VERSION 5.8 ;
BUSBITCHARS "[]" ;
DIVIDERCHAR "/" ;
UNITS
    DATABASE MICRONS 1000 ;
END UNITS

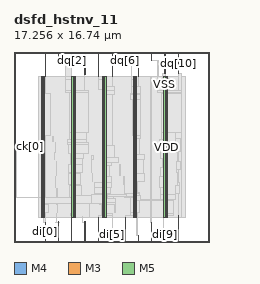
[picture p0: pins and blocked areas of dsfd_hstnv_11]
MACRO dsfd_hstnv_11
  FOREIGN dsfd_hstnv_11 0 0 ;
  CLASS BLOCK ;
  SIZE 17.256 BY 16.74 ;
  PIN ck[0]
    DIRECTION INPUT ;
    USE SIGNAL ;
    PORT
      LAYER M4 ;
        RECT  0 8.4 0.192 8.424 ;
    END
    PORT
      LAYER M4 ;
        RECT  0.156 8.4 0.275 8.424 ;
    END
  END ck[0]
  PIN di[0]
    DIRECTION INPUT ;
    USE SIGNAL ;
    PORT
      LAYER M3 ;
        RECT  2.736 0 2.754 0.144 ;
    END
    PORT
      LAYER M3 ;
        RECT  2.736 0.108 2.754 1.723 ;
    END
  END di[0]
  PIN di[10]
    DIRECTION INPUT ;
    USE SIGNAL ;
    PORT
      LAYER M3 ;
        RECT  14.508 0 14.526 0.144 ;
    END
    PORT
      LAYER M3 ;
        RECT  14.508 0.108 14.526 2.291 ;
    END
  END di[10]
  PIN di[1]
    DIRECTION INPUT ;
    USE SIGNAL ;
    PORT
      LAYER M5 ;
        RECT  3.936 0 3.96 0.192 ;
    END
    PORT
      LAYER M5 ;
        RECT  3.936 0.144 3.96 1.763 ;
    END
  END di[1]
  PIN di[2]
    DIRECTION INPUT ;
    USE SIGNAL ;
    PORT
      LAYER M3 ;
        RECT  5.076 0 5.094 0.144 ;
    END
    PORT
      LAYER M3 ;
        RECT  5.076 0.108 5.094 2.143 ;
    END
  END di[2]
  PIN di[3]
    DIRECTION INPUT ;
    USE SIGNAL ;
    PORT
      LAYER M5 ;
        RECT  6.24 0 6.264 0.192 ;
    END
    PORT
      LAYER M5 ;
        RECT  6.24 0.144 6.264 1.763 ;
    END
  END di[3]
  PIN di[4]
    DIRECTION INPUT ;
    USE SIGNAL ;
    PORT
      LAYER M3 ;
        RECT  7.452 0 7.47 0.144 ;
    END
    PORT
      LAYER M3 ;
        RECT  7.452 0.108 7.47 2.143 ;
    END
  END di[4]
  PIN di[5]
    DIRECTION INPUT ;
    USE SIGNAL ;
    PORT
      LAYER M5 ;
        RECT  8.64 0 8.664 0.192 ;
    END
    PORT
      LAYER M5 ;
        RECT  8.64 0.144 8.664 0.611 ;
    END
  END di[5]
  PIN di[6]
    DIRECTION INPUT ;
    USE SIGNAL ;
    PORT
      LAYER M3 ;
        RECT  9.792 0 9.81 0.144 ;
    END
    PORT
      LAYER M3 ;
        RECT  9.792 0.108 9.81 2.143 ;
    END
  END di[6]
  PIN di[7]
    DIRECTION INPUT ;
    USE SIGNAL ;
    PORT
      LAYER M5 ;
        RECT  10.944 0 10.968 0.192 ;
    END
    PORT
      LAYER M5 ;
        RECT  10.944 0.144 10.968 0.611 ;
    END
  END di[7]
  PIN di[8]
    DIRECTION INPUT ;
    USE SIGNAL ;
    PORT
      LAYER M3 ;
        RECT  12.132 0 12.15 0.144 ;
    END
    PORT
      LAYER M3 ;
        RECT  12.132 0.108 12.15 1.723 ;
    END
  END di[8]
  PIN di[9]
    DIRECTION INPUT ;
    USE SIGNAL ;
    PORT
      LAYER M5 ;
        RECT  13.296 0 13.32 0.192 ;
    END
    PORT
      LAYER M5 ;
        RECT  13.296 0.144 13.32 0.611 ;
    END
  END di[9]
  PIN dq[0]
    DIRECTION OUTPUT ;
    USE SIGNAL ;
    PORT
      LAYER M3 ;
        RECT  2.736 16.596 2.754 16.74 ;
    END
    PORT
      LAYER M3 ;
        RECT  2.736 14.597 2.754 16.62 ;
    END
  END dq[0]
  PIN dq[10]
    DIRECTION OUTPUT ;
    USE SIGNAL ;
    PORT
      LAYER M3 ;
        RECT  14.508 16.596 14.526 16.74 ;
    END
    PORT
      LAYER M3 ;
        RECT  14.508 14.864 14.526 16.62 ;
    END
  END dq[10]
  PIN dq[1]
    DIRECTION OUTPUT ;
    USE SIGNAL ;
    PORT
      LAYER M5 ;
        RECT  3.936 16.548 3.96 16.74 ;
    END
    PORT
      LAYER M5 ;
        RECT  3.936 15.973 3.96 16.592 ;
    END
  END dq[1]
  PIN dq[2]
    DIRECTION OUTPUT ;
    USE SIGNAL ;
    PORT
      LAYER M3 ;
        RECT  5.076 16.596 5.094 16.74 ;
    END
    PORT
      LAYER M3 ;
        RECT  5.076 16.013 5.094 16.62 ;
    END
  END dq[2]
  PIN dq[3]
    DIRECTION OUTPUT ;
    USE SIGNAL ;
    PORT
      LAYER M5 ;
        RECT  6.24 16.548 6.264 16.74 ;
    END
    PORT
      LAYER M5 ;
        RECT  6.24 14.773 6.264 16.592 ;
    END
  END dq[3]
  PIN dq[4]
    DIRECTION OUTPUT ;
    USE SIGNAL ;
    PORT
      LAYER M3 ;
        RECT  7.452 16.596 7.47 16.74 ;
    END
    PORT
      LAYER M3 ;
        RECT  7.452 14.597 7.47 16.62 ;
    END
  END dq[4]
  PIN dq[5]
    DIRECTION OUTPUT ;
    USE SIGNAL ;
    PORT
      LAYER M5 ;
        RECT  8.64 16.548 8.664 16.74 ;
    END
    PORT
      LAYER M5 ;
        RECT  8.64 14.603 8.664 16.592 ;
    END
  END dq[5]
  PIN dq[6]
    DIRECTION OUTPUT ;
    USE SIGNAL ;
    PORT
      LAYER M3 ;
        RECT  9.792 16.596 9.81 16.74 ;
    END
    PORT
      LAYER M3 ;
        RECT  9.792 15.989 9.81 16.62 ;
    END
  END dq[6]
  PIN dq[7]
    DIRECTION OUTPUT ;
    USE SIGNAL ;
    PORT
      LAYER M5 ;
        RECT  10.944 16.548 10.968 16.74 ;
    END
    PORT
      LAYER M5 ;
        RECT  10.944 14.603 10.968 16.592 ;
    END
  END dq[7]
  PIN dq[8]
    DIRECTION OUTPUT ;
    USE SIGNAL ;
    PORT
      LAYER M3 ;
        RECT  12.132 16.596 12.15 16.74 ;
    END
    PORT
      LAYER M3 ;
        RECT  12.132 15.989 12.15 16.62 ;
    END
  END dq[8]
  PIN dq[9]
    DIRECTION OUTPUT ;
    USE SIGNAL ;
    PORT
      LAYER M5 ;
        RECT  13.296 16.548 13.32 16.74 ;
    END
    PORT
      LAYER M5 ;
        RECT  13.296 14.867 13.32 16.592 ;
    END
  END dq[9]
  PIN VDD
    DIRECTION INOUT ;
    USE POWER ;
    PORT
      LAYER M5 ;
        RECT  13.392 2.151 13.512 14.589 ;
        RECT  10.692 2.151 10.812 14.589 ;
        RECT  7.992 2.151 8.112 14.589 ;
        RECT  5.292 2.151 5.412 14.589 ;
        RECT  2.592 2.151 2.712 14.589 ;
    END
  END VDD
  PIN VSS
    DIRECTION INOUT ;
    USE GROUND ;
    PORT
      LAYER M5 ;
        RECT  13.2 2.137 13.32 14.603 ;
        RECT  10.5 2.137 10.62 14.603 ;
        RECT  7.8 2.137 7.92 14.603 ;
        RECT  5.1 2.137 5.22 14.603 ;
        RECT  2.4 2.137 2.52 14.603 ;
    END
  END VSS
  # OT_OBS_CLOSED layer=M5 d_um=1.536 added=0
  OBS
    LAYER RVTN ;
     RECT  2.16 2.16 15.066 2.295 ;
     RECT  2.16 2.565 15.066 2.835 ;
     RECT  2.16 3.105 15.066 3.375 ;
     RECT  2.16 3.645 15.066 3.915 ;
     RECT  2.16 4.185 15.066 4.455 ;
     RECT  2.16 4.725 15.066 4.995 ;
     RECT  2.16 5.265 15.066 5.535 ;
     RECT  2.16 5.805 15.066 6.075 ;
     RECT  2.16 6.345 15.066 6.615 ;
     RECT  2.16 6.885 15.066 7.155 ;
     RECT  2.16 7.425 15.066 7.695 ;
     RECT  2.16 7.965 15.066 8.235 ;
     RECT  2.16 8.505 15.066 8.775 ;
     RECT  2.16 9.045 15.066 9.315 ;
     RECT  2.16 9.585 15.066 9.855 ;
     RECT  2.16 10.125 15.066 10.395 ;
     RECT  2.16 10.665 15.066 10.935 ;
     RECT  2.16 11.205 15.066 11.475 ;
     RECT  2.16 11.745 15.066 12.015 ;
     RECT  2.16 12.285 15.066 12.555 ;
     RECT  2.16 12.825 15.066 13.095 ;
     RECT  2.16 13.365 15.066 13.635 ;
     RECT  2.16 13.905 15.066 14.175 ;
     RECT  2.16 14.445 15.066 14.58 ;
    LAYER RVTP ;
     RECT  2.16 2.295 15.066 2.565 ;
     RECT  2.16 2.835 15.066 3.105 ;
     RECT  2.16 3.375 15.066 3.645 ;
     RECT  2.16 3.915 15.066 4.185 ;
     RECT  2.16 4.455 15.066 4.725 ;
     RECT  2.16 4.995 15.066 5.265 ;
     RECT  2.16 5.535 15.066 5.805 ;
     RECT  2.16 6.075 15.066 6.345 ;
     RECT  2.16 6.615 15.066 6.885 ;
     RECT  2.16 7.155 15.066 7.425 ;
     RECT  2.16 7.695 15.066 7.965 ;
     RECT  2.16 8.235 15.066 8.505 ;
     RECT  2.16 8.775 15.066 9.045 ;
     RECT  2.16 9.315 15.066 9.585 ;
     RECT  2.16 9.855 15.066 10.125 ;
     RECT  2.16 10.395 15.066 10.665 ;
     RECT  2.16 10.935 15.066 11.205 ;
     RECT  2.16 11.475 15.066 11.745 ;
     RECT  2.16 12.015 15.066 12.285 ;
     RECT  2.16 12.555 15.066 12.825 ;
     RECT  2.16 13.095 15.066 13.365 ;
     RECT  2.16 13.635 15.066 13.905 ;
     RECT  2.16 14.175 15.066 14.445 ;
    LAYER M1 ;
     RECT  2.16 2.151 15.066 14.589 ;
    LAYER M2 ;
     RECT  2.16 2.151 2.623 14.589 ;
     RECT  2.623 1.728 2.759 14.589 ;
     RECT  9.787 15.966 10.355 15.984 ;
     RECT  2.759 2.151 12.019 14.589 ;
     RECT  12.019 1.728 12.155 14.589 ;
     RECT  12.127 15.966 12.695 15.984 ;
     RECT  12.155 2.151 14.503 14.589 ;
     RECT  14.503 2.151 14.747 14.859 ;
     RECT  14.747 2.151 15.066 14.589 ;
    LAYER M3 ;
     RECT  12.024 1.723 12.15 1.751 ;
     RECT  2.628 1.723 2.754 2.143 ;
     RECT  10.836 0.571 10.854 2.143 ;
     RECT  13.176 0.571 13.194 2.143 ;
     RECT  3.708 1.723 3.726 2.255 ;
     RECT  6.012 1.723 6.03 2.255 ;
     RECT  12.024 1.751 12.078 2.255 ;
     RECT  13.176 2.143 13.305 2.255 ;
     RECT  7.452 2.143 7.905 2.291 ;
     RECT  9.792 2.143 10.854 2.291 ;
     RECT  5.076 2.143 5.205 2.371 ;
     RECT  7.704 2.291 7.905 2.371 ;
     RECT  8.64 0.571 8.658 2.371 ;
     RECT  10.224 2.291 10.854 2.371 ;
     RECT  13.212 2.255 13.305 2.371 ;
     RECT  5.004 2.371 5.205 2.413 ;
     RECT  3.744 2.371 3.762 2.489 ;
     RECT  5.004 2.413 5.397 2.489 ;
     RECT  7.704 2.371 8.658 2.489 ;
     RECT  13.212 2.371 14.094 2.489 ;
     RECT  2.415 2.143 2.754 2.641 ;
     RECT  10.224 2.371 10.89 2.641 ;
     RECT  3.852 2.641 3.87 3.271 ;
     RECT  2.415 2.641 3.006 3.299 ;
     RECT  7.704 2.489 8.097 3.307 ;
     RECT  8.892 2.641 8.91 3.307 ;
     RECT  7.704 3.307 8.91 3.343 ;
     RECT  3.78 3.271 3.87 3.403 ;
     RECT  5.115 2.489 5.397 3.403 ;
     RECT  2.415 3.299 2.862 3.437 ;
     RECT  7.524 3.343 8.91 3.437 ;
     RECT  12.06 2.255 12.078 3.569 ;
     RECT  13.215 2.489 14.094 3.691 ;
     RECT  3.78 3.403 3.942 3.721 ;
     RECT  5.004 3.403 5.706 3.721 ;
     RECT  13.104 3.691 14.094 3.721 ;
     RECT  11.916 3.685 12.006 3.725 ;
     RECT  5.004 3.721 5.922 3.811 ;
     RECT  3.78 3.721 4.086 3.839 ;
     RECT  7.815 3.437 8.91 3.839 ;
     RECT  3.78 3.839 3.942 3.875 ;
     RECT  10.224 2.641 11.034 3.955 ;
     RECT  7.815 3.839 8.73 4.013 ;
     RECT  6.66 2.263 6.678 4.027 ;
     RECT  9.72 3.955 11.034 4.075 ;
     RECT  6.66 4.027 6.858 4.109 ;
     RECT  6.84 4.109 6.858 4.157 ;
     RECT  12.888 3.721 14.238 4.217 ;
     RECT  9.72 4.075 11.07 4.259 ;
     RECT  7.815 4.013 8.514 4.261 ;
     RECT  14.22 4.217 14.238 4.261 ;
     RECT  10.515 4.259 11.07 4.379 ;
     RECT  3.78 3.875 3.798 4.685 ;
     RECT  7.092 4.261 8.514 4.801 ;
     RECT  12.888 4.217 13.497 4.801 ;
     RECT  4.86 3.811 5.922 4.955 ;
     RECT  14.22 4.261 14.562 4.955 ;
     RECT  9.72 4.259 9.738 4.991 ;
     RECT  4.86 4.955 5.886 5.071 ;
     RECT  7.092 4.801 8.586 5.225 ;
     RECT  14.364 4.955 14.562 5.225 ;
     RECT  11.988 3.725 12.006 5.261 ;
     RECT  10.515 4.379 10.89 5.341 ;
     RECT  3.636 4.801 3.654 5.765 ;
     RECT  7.815 5.225 8.586 5.765 ;
     RECT  9.684 5.071 9.702 5.765 ;
     RECT  12.816 4.801 13.497 5.765 ;
     RECT  4.788 5.071 5.886 6.035 ;
     RECT  6.876 5.341 6.894 6.035 ;
     RECT  10.515 5.341 11.502 6.035 ;
     RECT  4.824 6.035 5.886 6.151 ;
     RECT  14.364 5.225 14.526 6.151 ;
     RECT  14.292 6.151 14.526 6.421 ;
     RECT  12.924 5.765 13.497 6.575 ;
     RECT  7.815 5.765 8.406 6.781 ;
     RECT  4.824 6.151 5.994 6.845 ;
     RECT  9.324 5.881 9.342 6.845 ;
     RECT  7.815 6.781 8.586 6.961 ;
     RECT  3.708 5.881 3.726 7.115 ;
     RECT  14.292 6.421 14.634 7.115 ;
     RECT  6.84 6.151 6.858 7.231 ;
     RECT  10.515 6.035 11.43 7.231 ;
     RECT  4.968 6.845 5.994 7.321 ;
     RECT  13.104 6.575 13.497 7.321 ;
     RECT  7.815 6.961 9.234 7.421 ;
     RECT  6.84 7.231 6.966 7.619 ;
     RECT  10.515 7.231 11.502 7.691 ;
     RECT  4.968 7.321 6.102 7.771 ;
     RECT  3.528 7.231 3.546 7.861 ;
     RECT  14.4 7.115 14.454 7.861 ;
     RECT  3.528 7.861 3.654 7.889 ;
     RECT  14.256 7.861 14.454 7.933 ;
     RECT  7.815 7.421 8.874 8.465 ;
     RECT  4.788 7.771 6.57 8.581 ;
     RECT  12.888 7.321 13.497 8.581 ;
     RECT  3.636 7.889 3.654 8.735 ;
     RECT  4.716 8.581 6.57 8.735 ;
     RECT  4.716 8.735 6.426 9.005 ;
     RECT  12.816 8.581 13.497 9.005 ;
     RECT  10.515 7.691 11.07 9.085 ;
     RECT  14.256 7.933 14.67 9.085 ;
     RECT  3.42 8.851 3.438 9.275 ;
     RECT  2.415 3.437 2.697 9.391 ;
     RECT  10.515 9.085 11.106 9.391 ;
     RECT  4.932 9.005 6.426 9.661 ;
     RECT  13.032 9.005 13.497 9.661 ;
     RECT  14.256 9.085 14.778 9.661 ;
     RECT  10.404 9.391 11.106 12.559 ;
     RECT  7.815 8.465 8.694 12.991 ;
     RECT  10.26 12.559 11.106 12.991 ;
     RECT  2.415 9.391 3.186 13.055 ;
     RECT  10.26 12.991 11.142 13.055 ;
     RECT  13.032 9.661 14.778 13.055 ;
     RECT  4.932 9.661 6.534 13.171 ;
     RECT  13.032 13.055 14.742 13.171 ;
     RECT  4.572 13.171 6.534 13.325 ;
     RECT  7.815 12.991 8.874 13.325 ;
     RECT  12.672 13.171 14.742 13.325 ;
     RECT  7.815 13.325 8.097 13.441 ;
     RECT  8.856 13.325 8.874 13.709 ;
     RECT  10.332 13.055 11.142 13.709 ;
     RECT  4.572 13.325 5.397 14.327 ;
     RECT  7.452 13.441 8.097 14.327 ;
     RECT  10.332 13.709 10.797 14.327 ;
     RECT  12.672 13.325 13.662 14.429 ;
     RECT  2.415 13.055 2.754 14.597 ;
     RECT  4.572 14.327 5.205 14.597 ;
     RECT  7.452 14.327 7.905 14.597 ;
     RECT  10.332 14.327 10.605 14.597 ;
     RECT  12.672 14.429 13.305 14.597 ;
     RECT  6.228 13.325 6.246 14.813 ;
     RECT  14.724 13.325 14.742 14.836 ;
     RECT  14.508 14.836 14.742 14.864 ;
     RECT  10.332 14.597 10.35 15.961 ;
     RECT  12.672 14.597 12.69 15.961 ;
     RECT  9.792 15.961 10.35 15.989 ;
     RECT  12.132 15.961 12.69 15.989 ;
     RECT  4.572 14.597 5.094 16.013 ;
    LAYER M4 ;
     RECT  0.229 3.888 2.408 3.912 ;
     RECT  2.408 2.148 2.512 14.592 ;
     RECT  2.512 2.418 2.704 14.322 ;
     RECT  3.697 1.728 3.971 1.752 ;
     RECT  3.925 15.984 4.601 16.008 ;
     RECT  2.704 3.408 5.108 3.912 ;
     RECT  5.108 2.148 5.212 14.592 ;
     RECT  5.212 2.148 5.404 14.322 ;
     RECT  6.001 1.728 6.275 1.752 ;
     RECT  6.217 14.784 6.301 14.808 ;
     RECT  5.404 3.408 6.829 4.056 ;
     RECT  6.829 3.408 7.808 4.152 ;
     RECT  7.808 2.148 7.912 14.592 ;
     RECT  7.912 2.418 8.104 14.322 ;
     RECT  8.104 3.888 8.273 4.152 ;
     RECT  8.629 0.576 8.713 0.6 ;
     RECT  8.104 13.68 8.885 13.704 ;
     RECT  8.273 3.984 9.889 4.152 ;
     RECT  9.889 3.984 10.508 4.248 ;
     RECT  10.508 2.148 10.612 14.592 ;
     RECT  10.612 2.418 10.804 14.322 ;
     RECT  10.825 0.576 10.979 0.6 ;
     RECT  10.804 3.696 11.081 4.248 ;
     RECT  11.081 3.696 11.123 4.104 ;
     RECT  10.804 13.68 11.153 13.704 ;
     RECT  11.123 3.696 13.208 3.72 ;
     RECT  13.093 14.4 13.208 14.856 ;
     RECT  13.208 2.148 13.312 14.856 ;
     RECT  13.165 0.576 13.331 0.6 ;
     RECT  13.312 2.418 13.331 14.856 ;
     RECT  13.331 2.418 13.504 14.424 ;
     RECT  13.504 14.4 13.673 14.424 ;
    LAYER M5 ;
     RECT  2.4 2.137 2.52 2.151 ;
     RECT  5.1 2.137 5.22 2.151 ;
     RECT  7.8 2.137 7.92 2.151 ;
     RECT  10.5 2.137 10.62 2.151 ;
     RECT  13.2 2.137 13.32 2.151 ;
     RECT  10.5 2.151 10.812 3.685 ;
     RECT  10.5 3.685 11.112 4.115 ;
     RECT  0.24 3.877 0.264 8.435 ;
     RECT  7.8 2.151 8.112 13.669 ;
     RECT  10.5 4.115 10.812 13.669 ;
     RECT  13.2 2.151 13.512 14.389 ;
     RECT  2.4 2.151 2.712 14.589 ;
     RECT  5.1 2.151 5.412 14.589 ;
     RECT  13.104 14.389 13.512 14.589 ;
     RECT  2.4 14.589 2.52 14.603 ;
     RECT  5.1 14.589 5.22 14.603 ;
     RECT  7.8 13.669 8.664 14.603 ;
     RECT  10.5 13.669 10.968 14.603 ;
     RECT  13.104 14.589 13.32 14.867 ;
  END
END dsfd_hstnv_11
END LIBRARY
